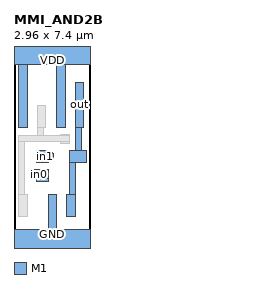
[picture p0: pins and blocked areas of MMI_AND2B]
MACRO MMI_AND2B
	CLASS CORE ;
	FOREIGN MMI_AND2B 0 0 ;
	SIZE 2.96 BY 7.4 ;
	SYMMETRY X Y ;
	SITE CORE1 ;
	PIN out
		DIRECTION output ;
		USE SIGNAL ;
		PORT
			LAYER M1 ;
			RECT 2.38 4.465 2.72 6.225 ;
			LAYER M1 ;
			RECT 2.38 3.555 2.61 4.465 ;
			LAYER M1 ;
			RECT 2.16 3.105 2.815 3.555 ;
			LAYER M1 ;
			RECT 2.16 1.85 2.39 3.105 ;
			LAYER M1 ;
			RECT 2.05 1.01 2.39 1.85 ;
		END
		AntennaDiffArea 1.3248 ;
	END out
	PIN in1
		DIRECTION input ;
		USE SIGNAL ;
		PORT
			LAYER M1 ;
			RECT 0.885 3.5 1.335 3.555 ;
			LAYER M1 ;
			RECT 0.885 3.445 1.48 3.5 ;
			LAYER M1 ;
			RECT 0.885 3.215 1.545 3.445 ;
			LAYER M1 ;
			RECT 0.885 3.16 1.48 3.215 ;
			LAYER M1 ;
			RECT 0.885 3.105 1.335 3.16 ;
		END
		AntennaGateArea 0.3312 ;
	END in1
	PIN GND
		DIRECTION inout ;
		USE GROUND ;
		PORT
			LAYER M1 ;
			RECT 1.33 0.5 1.67 1.85 ;
			LAYER M1 ;
			RECT 0 -0.5 2.96 0.5 ;
		END
	END GND
	PIN VDD
		DIRECTION inout ;
		USE POWER ;
		PORT
			LAYER M1 ;
			RECT 0 6.9 2.96 7.9 ;
			LAYER M1 ;
			RECT 0.18 4.465 0.52 6.9 ;
			LAYER M1 ;
			RECT 1.66 4.465 2 6.9 ;
		END
	END VDD
	PIN in0
		DIRECTION input ;
		USE SIGNAL ;
		PORT
			LAYER M1 ;
			RECT 0.885 2.81 1.335 2.815 ;
			LAYER M1 ;
			RECT 0.64 2.47 1.335 2.81 ;
			LAYER M1 ;
			RECT 0.885 2.365 1.335 2.47 ;
		END
		AntennaGateArea 0.3312 ;
	END in0
	OBS
		LAYER M1 ;
		RECT 0.9 4.465 1.24 5.305 ;
		LAYER M1 ;
		RECT 0.9 4.135 1.13 4.465 ;
		LAYER M1 ;
		RECT 1.81 4.135 2.15 4.19 ;
		LAYER M1 ;
		RECT 0.18 3.905 2.15 4.135 ;
		LAYER M1 ;
		RECT 0.18 1.85 0.41 3.905 ;
		LAYER M1 ;
		RECT 1.81 3.85 2.15 3.905 ;
		LAYER M1 ;
		RECT 0.18 1.01 0.52 1.85 ;
	END
END MMI_AND2B
